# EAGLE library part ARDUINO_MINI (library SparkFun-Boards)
Arduino Pro Mini footprint

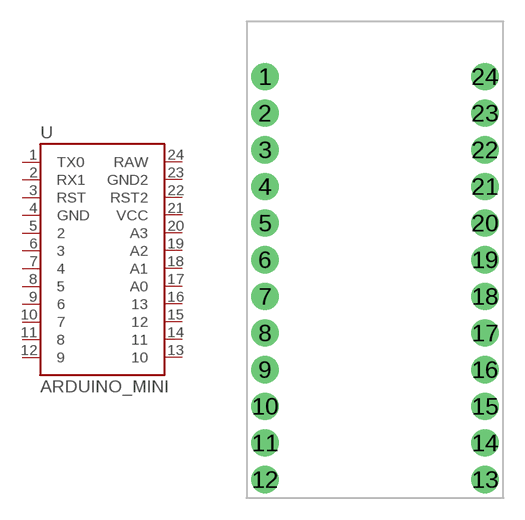
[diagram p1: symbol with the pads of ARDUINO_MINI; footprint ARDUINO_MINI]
Designator prefix -

## ARDUINO_MINI  [ARDUINO_MINI]
1  TX0
2  RX1
3  RST
4  GND
5  2
6  3
7  4
8  5
9  6
10  7
11  8
12  9
13  10
14  11
15  12
16  13
17  A0
18  A1
19  A2
20  A3
21  VCC
22  RST2
23  GND2
24  RAW

## Footprint ARDUINO_MINI (pad centres in mm)
drill 1.016 pad 1.88: 1 -7.62,12.7; 2 -7.62,10.16; 3 -7.62,7.62; 4 -7.62,5.08; 5 -7.62,2.54; 6 -7.62,0; 7 -7.62,-2.54; 8 -7.62,-5.08; 9 -7.62,-7.62; 10 -7.62,-10.16; 11 -7.62,-12.7; 12 -7.62,-15.24; 13 7.62,-15.24; 14 7.62,-12.7; 15 7.62,-10.16; 16 7.62,-7.62; 17 7.62,-5.08; 18 7.62,-2.54; 19 7.62,0; 20 7.62,2.54; 21 7.62,5.08; 22 7.62,7.62; 23 7.62,10.16; 24 7.62,12.7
